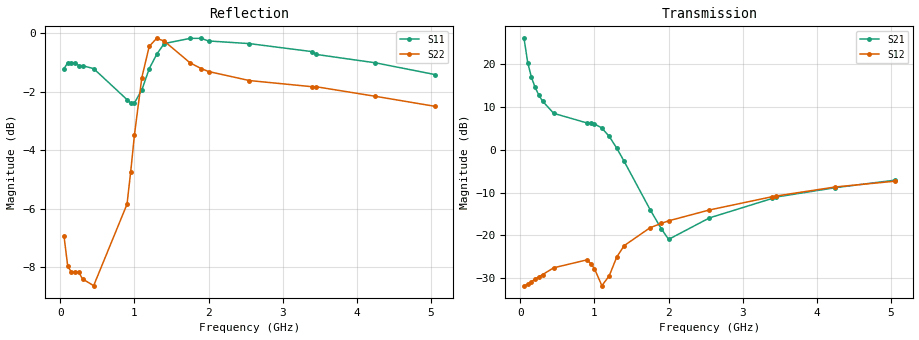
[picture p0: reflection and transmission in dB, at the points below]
!AT-33225
!S-PARAMETERS at Vce=3.6V  Ic=50mA.  LAST UPDATED 08-05-96
# ghz s ma r 50
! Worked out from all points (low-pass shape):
!   101 points, 50 MHz to 5.05 GHz, reference 50 ohm
!   highest |S21| = 25.89 dB at 50 MHz (marker M1); lowest = -20.9 dB at 2 GHz (marker M2)
!   |S21| within 3 dB of the highest: start of sweep to 76.45 MHz
!   lowest |S11| = -2.4 dB at 950 MHz (marker M3), VSWR 7.33, Z = 6.85 + j3.43 ohm
!   |S11| at or under -10 dB: nowhere
!   |S22| runs from -8.6 to -0.2 dB; largest |S21 - S12| = 20
!   S11 on the Smith chart (normalised r, x): 50 MHz: 0.07, -0.21; 300 MHz: 0.06, +0.01; 1.9 GHz: 0.01, +0.18; 3.45 GHz: 0.05, +0.37; 5.05 GHz: 0.11, +0.60
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0.05  0.87 -156.0  19.71 102.0  0.026 23.0  0.45 -130.0
0.1  0.89 -169.0  10.26 91.0  0.027 22.0  0.4 -152.0
0.15  0.89 -174.0  6.94 85.0  0.029 25.0  0.39 -160.0
0.2  0.89 -177.0  5.28 81.0  0.031 28.0  0.39 -164.0
0.25  0.88 -179.0  4.3 77.0  0.033 31.0  0.39 -166.0
0.3  0.88 179.0  3.66 73.0  0.035 34.0  0.38 -166.0
0.45  0.87 175.0  2.64 61.0  0.042 39.0  0.37 -165.0
0.9  0.77 171.0  2.04 11.0  0.052 29.0  0.51 -136.0
0.95  0.76 172.0  2.02 2.0  0.047 27.0  0.58 -135.0
1  0.76 174.0  1.99 -8.0  0.041 26.0  0.67 -136.0
1.1  0.8 177.0  1.78 -32.0  0.026 46.0  0.84 -144.0
1.2  0.87 177.0  1.42 -55.0  0.034 89.0  0.95 -155.0
1.3  0.92 175.0  1.04 -75.0  0.056 96.0  0.98 -165.0
1.4  0.96 172.0  0.73 -90.0  0.076 93.0  0.97 -173.0
1.75  0.98 163.0  0.2 -135.0  0.123 80.0  0.89 172.0
1.9  0.98 160.0  0.12 -164.0  0.138 76.0  0.87 169.0
2  0.97 158.0  0.09 170.0  0.148 74.0  0.86 167.0
2.55  0.96 151.0  0.16 81.0  0.198 64.0  0.83 156.0
3.4  0.93 140.0  0.27 54.0  0.283 51.0  0.81 140.0
3.45  0.92 139.0  0.28 53.0  0.288 50.0  0.81 139.0
4.25  0.89 128.0  0.36 36.0  0.367 34.0  0.78 120.0
5.05  0.85 118.0  0.44 18.0  0.428 18.0  0.75 97.0
